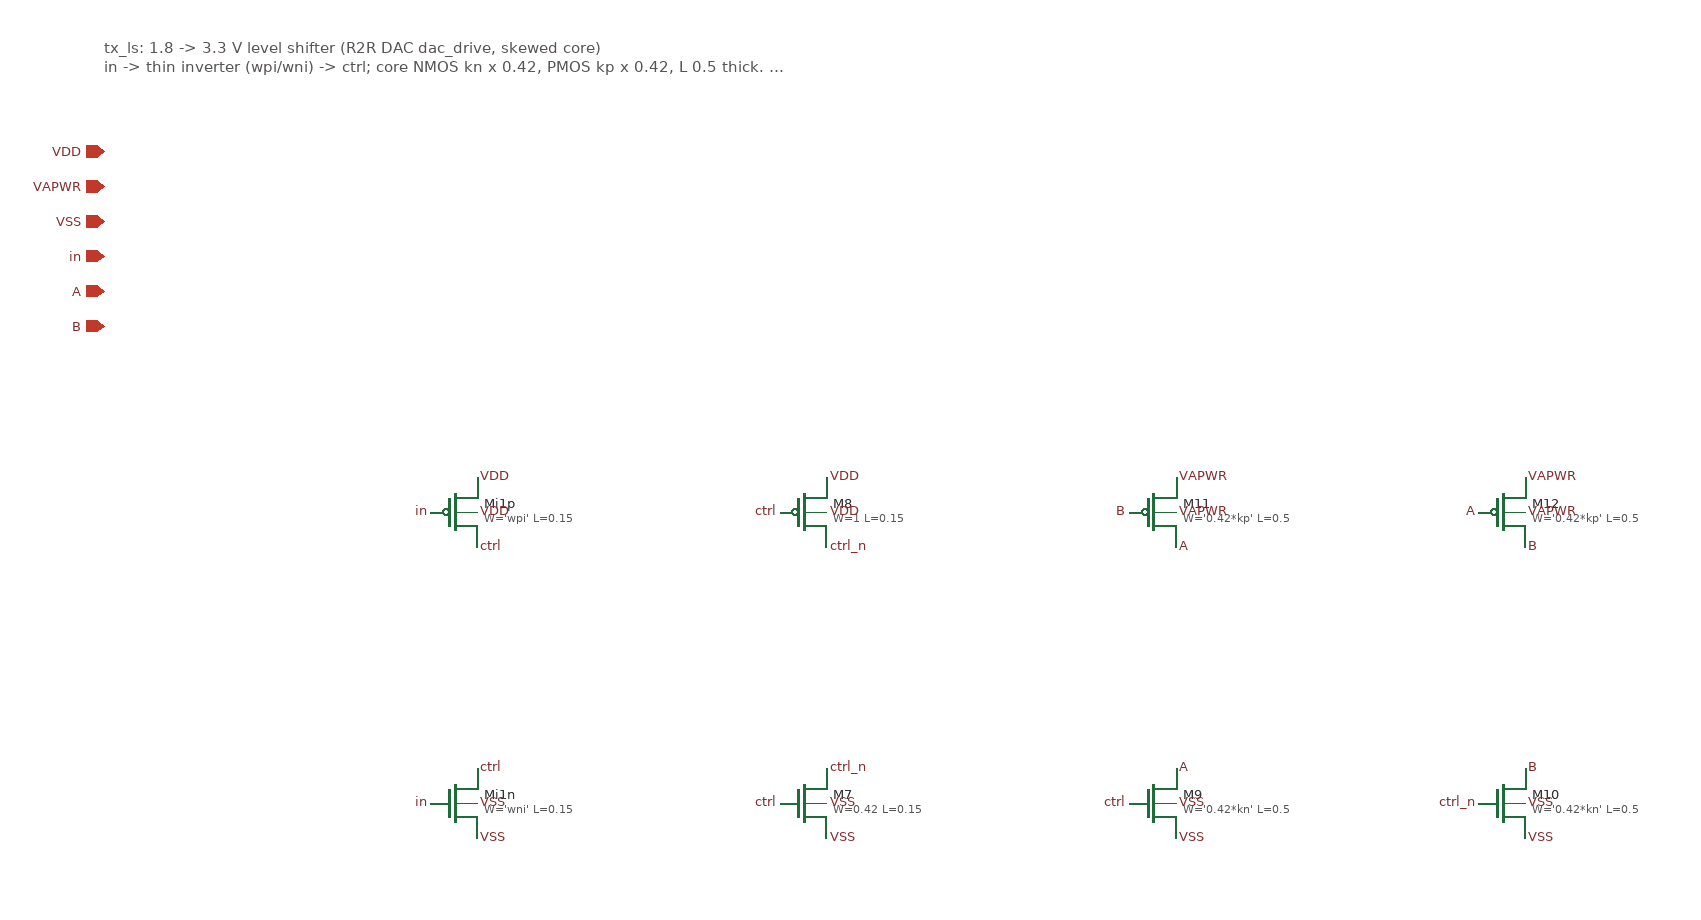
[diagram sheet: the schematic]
v {xschem version=3.4.5 file_version=1.2
}
G {}
K {}
V {}
S {}
E {}
T {tx_ls: 1.8 -> 3.3 V level shifter (R2R DAC dac_drive, skewed core)
in -> thin inverter (wpi/wni) -> ctrl; core NMOS kn x 0.42, PMOS kp x 0.42, L 0.5 thick. A = in, B = not in} -700 -560 0 0 0.4 0.4 {}
C {devices/iopin.sym} -700 -460 0 0 {name=p1
lab=VDD}
C {devices/iopin.sym} -700 -430 0 0 {name=p2
lab=VAPWR}
C {devices/iopin.sym} -700 -400 0 0 {name=p3
lab=VSS}
C {devices/iopin.sym} -700 -370 0 0 {name=p4
lab=in}
C {devices/iopin.sym} -700 -340 0 0 {name=p5
lab=A}
C {devices/iopin.sym} -700 -310 0 0 {name=p6
lab=B}
C {sky130_fd_pr/pfet_01v8.sym} -400 -150 0 0 {name=Mi1p
nf=1
mult=1
ad="'int((nf+1)/2) * W/nf * 0.29'"
pd="'2*int((nf+1)/2) * (W/nf + 0.29)'"
as="'int((nf+2)/2) * W/nf * 0.29'"
ps="'2*int((nf+2)/2) * (W/nf + 0.29)'"
nrd="'0.29 / W'"
nrs="'0.29 / W'"
sa=0
sb=0
sd=0
L=0.15
W='wpi'
model=pfet_01v8
spiceprefix=X}
C {devices/lab_pin.sym} -380 -120 0 1 {name=p7
sig_type=std_logic
lab=ctrl}
C {devices/lab_pin.sym} -420 -150 0 0 {name=p8
sig_type=std_logic
lab=in}
C {devices/lab_pin.sym} -380 -180 0 1 {name=p9
sig_type=std_logic
lab=VDD}
C {devices/lab_pin.sym} -380 -150 0 1 {name=p10
sig_type=std_logic
lab=VDD}
C {sky130_fd_pr/nfet_01v8.sym} -400 100 0 0 {name=Mi1n
nf=1
mult=1
ad="'int((nf+1)/2) * W/nf * 0.29'"
pd="'2*int((nf+1)/2) * (W/nf + 0.29)'"
as="'int((nf+2)/2) * W/nf * 0.29'"
ps="'2*int((nf+2)/2) * (W/nf + 0.29)'"
nrd="'0.29 / W'"
nrs="'0.29 / W'"
sa=0
sb=0
sd=0
L=0.15
W='wni'
model=nfet_01v8
spiceprefix=X}
C {devices/lab_pin.sym} -380 70 0 1 {name=p11
sig_type=std_logic
lab=ctrl}
C {devices/lab_pin.sym} -420 100 0 0 {name=p12
sig_type=std_logic
lab=in}
C {devices/lab_pin.sym} -380 130 0 1 {name=p13
sig_type=std_logic
lab=VSS}
C {devices/lab_pin.sym} -380 100 0 1 {name=p14
sig_type=std_logic
lab=VSS}
C {sky130_fd_pr/pfet_01v8_hvt.sym} -100 -150 0 0 {name=M8
nf=1
mult=1
ad="'int((nf+1)/2) * W/nf * 0.29'"
pd="'2*int((nf+1)/2) * (W/nf + 0.29)'"
as="'int((nf+2)/2) * W/nf * 0.29'"
ps="'2*int((nf+2)/2) * (W/nf + 0.29)'"
nrd="'0.29 / W'"
nrs="'0.29 / W'"
sa=0
sb=0
sd=0
L=0.15
W=1
model=pfet_01v8_hvt
spiceprefix=X}
C {devices/lab_pin.sym} -80 -120 0 1 {name=p15
sig_type=std_logic
lab=ctrl_n}
C {devices/lab_pin.sym} -120 -150 0 0 {name=p16
sig_type=std_logic
lab=ctrl}
C {devices/lab_pin.sym} -80 -180 0 1 {name=p17
sig_type=std_logic
lab=VDD}
C {devices/lab_pin.sym} -80 -150 0 1 {name=p18
sig_type=std_logic
lab=VDD}
C {sky130_fd_pr/nfet_01v8.sym} -100 100 0 0 {name=M7
nf=1
mult=1
ad="'int((nf+1)/2) * W/nf * 0.29'"
pd="'2*int((nf+1)/2) * (W/nf + 0.29)'"
as="'int((nf+2)/2) * W/nf * 0.29'"
ps="'2*int((nf+2)/2) * (W/nf + 0.29)'"
nrd="'0.29 / W'"
nrs="'0.29 / W'"
sa=0
sb=0
sd=0
L=0.15
W=0.42
model=nfet_01v8
spiceprefix=X}
C {devices/lab_pin.sym} -80 70 0 1 {name=p19
sig_type=std_logic
lab=ctrl_n}
C {devices/lab_pin.sym} -120 100 0 0 {name=p20
sig_type=std_logic
lab=ctrl}
C {devices/lab_pin.sym} -80 130 0 1 {name=p21
sig_type=std_logic
lab=VSS}
C {devices/lab_pin.sym} -80 100 0 1 {name=p22
sig_type=std_logic
lab=VSS}
C {sky130_fd_pr/nfet_g5v0d10v5.sym} 200 100 0 0 {name=M9
nf=1
mult=1
ad="'int((nf+1)/2) * W/nf * 0.29'"
pd="'2*int((nf+1)/2) * (W/nf + 0.29)'"
as="'int((nf+2)/2) * W/nf * 0.29'"
ps="'2*int((nf+2)/2) * (W/nf + 0.29)'"
nrd="'0.29 / W'"
nrs="'0.29 / W'"
sa=0
sb=0
sd=0
L=0.5
W='0.42*kn'
model=nfet_g5v0d10v5
spiceprefix=X}
C {devices/lab_pin.sym} 220 70 0 1 {name=p23
sig_type=std_logic
lab=A}
C {devices/lab_pin.sym} 180 100 0 0 {name=p24
sig_type=std_logic
lab=ctrl}
C {devices/lab_pin.sym} 220 130 0 1 {name=p25
sig_type=std_logic
lab=VSS}
C {devices/lab_pin.sym} 220 100 0 1 {name=p26
sig_type=std_logic
lab=VSS}
C {sky130_fd_pr/nfet_g5v0d10v5.sym} 500 100 0 0 {name=M10
nf=1
mult=1
ad="'int((nf+1)/2) * W/nf * 0.29'"
pd="'2*int((nf+1)/2) * (W/nf + 0.29)'"
as="'int((nf+2)/2) * W/nf * 0.29'"
ps="'2*int((nf+2)/2) * (W/nf + 0.29)'"
nrd="'0.29 / W'"
nrs="'0.29 / W'"
sa=0
sb=0
sd=0
L=0.5
W='0.42*kn'
model=nfet_g5v0d10v5
spiceprefix=X}
C {devices/lab_pin.sym} 520 70 0 1 {name=p27
sig_type=std_logic
lab=B}
C {devices/lab_pin.sym} 480 100 0 0 {name=p28
sig_type=std_logic
lab=ctrl_n}
C {devices/lab_pin.sym} 520 130 0 1 {name=p29
sig_type=std_logic
lab=VSS}
C {devices/lab_pin.sym} 520 100 0 1 {name=p30
sig_type=std_logic
lab=VSS}
C {sky130_fd_pr/pfet_g5v0d10v5.sym} 200 -150 0 0 {name=M11
nf=1
mult=1
ad="'int((nf+1)/2) * W/nf * 0.29'"
pd="'2*int((nf+1)/2) * (W/nf + 0.29)'"
as="'int((nf+2)/2) * W/nf * 0.29'"
ps="'2*int((nf+2)/2) * (W/nf + 0.29)'"
nrd="'0.29 / W'"
nrs="'0.29 / W'"
sa=0
sb=0
sd=0
L=0.5
W='0.42*kp'
model=pfet_g5v0d10v5
spiceprefix=X}
C {devices/lab_pin.sym} 220 -120 0 1 {name=p31
sig_type=std_logic
lab=A}
C {devices/lab_pin.sym} 180 -150 0 0 {name=p32
sig_type=std_logic
lab=B}
C {devices/lab_pin.sym} 220 -180 0 1 {name=p33
sig_type=std_logic
lab=VAPWR}
C {devices/lab_pin.sym} 220 -150 0 1 {name=p34
sig_type=std_logic
lab=VAPWR}
C {sky130_fd_pr/pfet_g5v0d10v5.sym} 500 -150 0 0 {name=M12
nf=1
mult=1
ad="'int((nf+1)/2) * W/nf * 0.29'"
pd="'2*int((nf+1)/2) * (W/nf + 0.29)'"
as="'int((nf+2)/2) * W/nf * 0.29'"
ps="'2*int((nf+2)/2) * (W/nf + 0.29)'"
nrd="'0.29 / W'"
nrs="'0.29 / W'"
sa=0
sb=0
sd=0
L=0.5
W='0.42*kp'
model=pfet_g5v0d10v5
spiceprefix=X}
C {devices/lab_pin.sym} 520 -120 0 1 {name=p35
sig_type=std_logic
lab=B}
C {devices/lab_pin.sym} 480 -150 0 0 {name=p36
sig_type=std_logic
lab=A}
C {devices/lab_pin.sym} 520 -180 0 1 {name=p37
sig_type=std_logic
lab=VAPWR}
C {devices/lab_pin.sym} 520 -150 0 1 {name=p38
sig_type=std_logic
lab=VAPWR}
